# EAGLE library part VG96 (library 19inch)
PCB EUROCARD, 96-pin type C/ABC, 2.54 mm

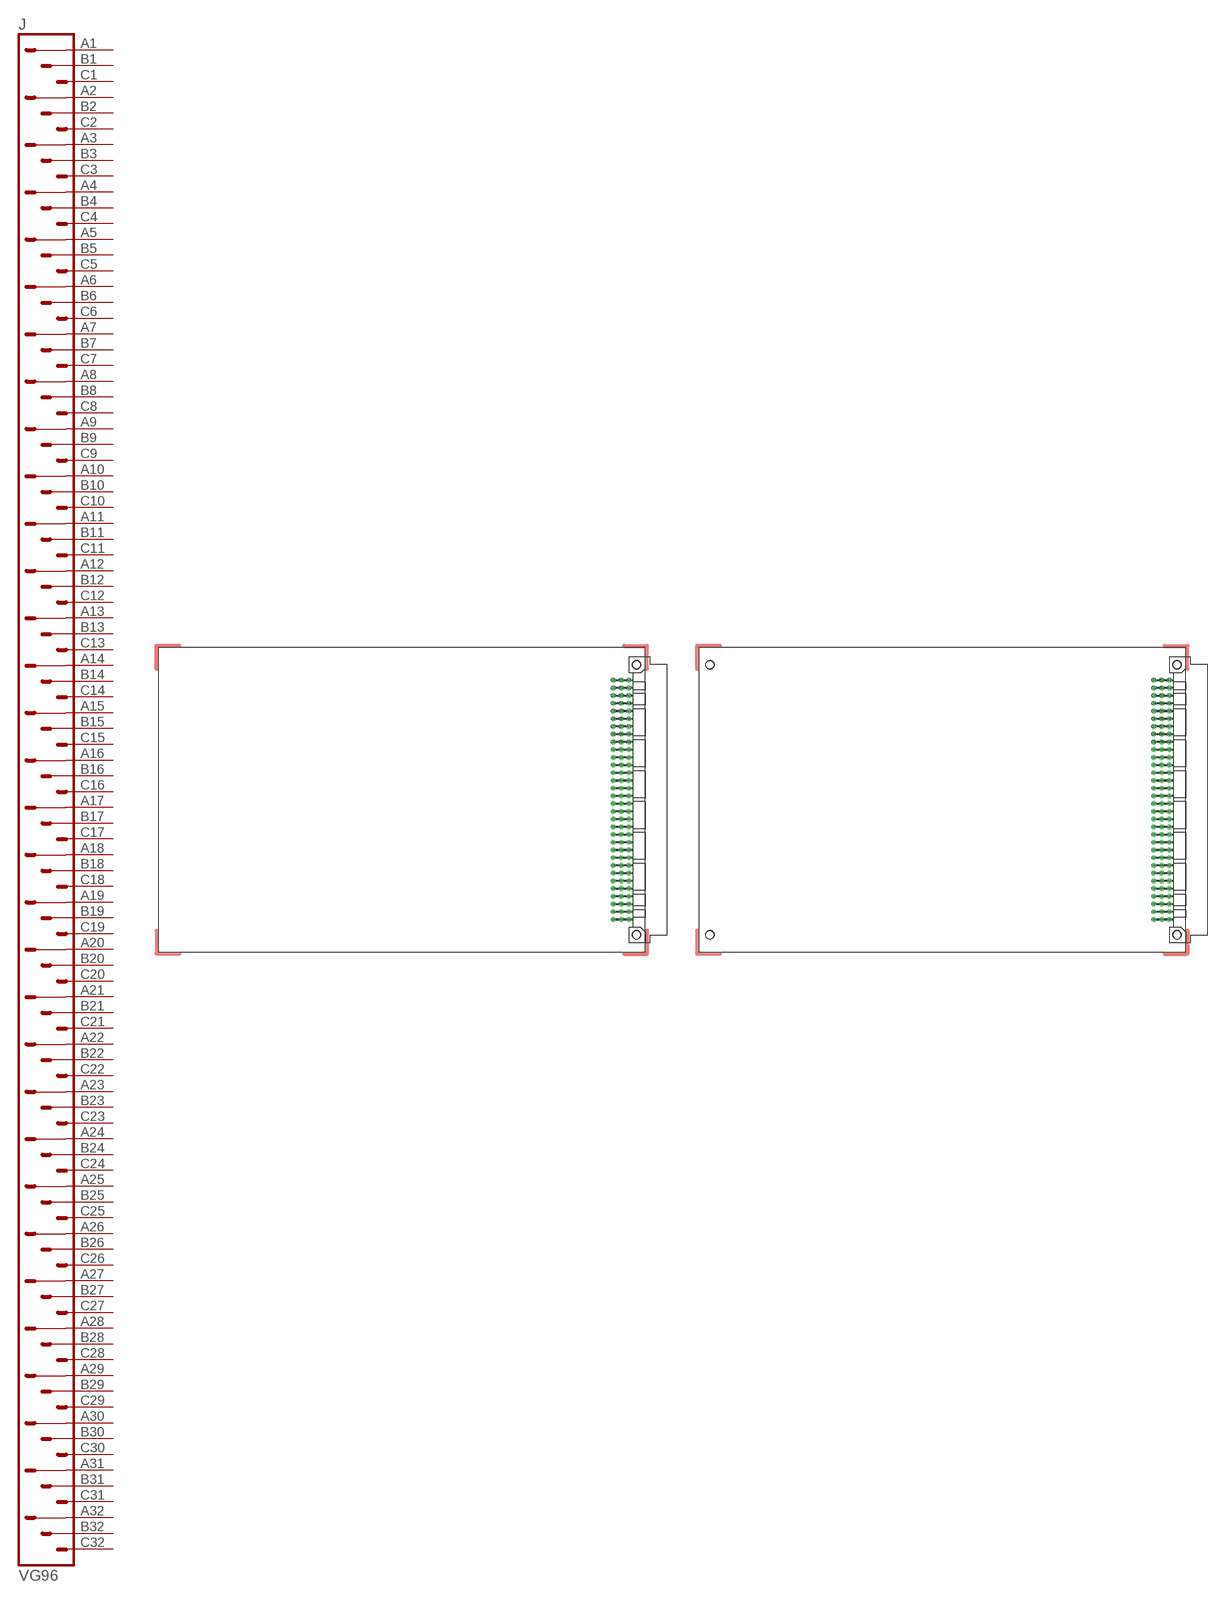
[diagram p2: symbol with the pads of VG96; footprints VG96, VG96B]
Designator prefix J

## VG96  [VG96]
A1  A1  pas
A2  A2  pas
A3  A3  pas
A4  A4  pas
A5  A5  pas
A6  A6  pas
A7  A7  pas
A8  A8  pas
A9  A9  pas
A10  A10  pas
A11  A11  pas
A12  A12  pas
A13  A13  pas
A14  A14  pas
A15  A15  pas
A16  A16  pas
A17  A17  pas
A18  A18  pas
A19  A19  pas
A20  A20  pas
A21  A21  pas
A22  A22  pas
A23  A23  pas
A24  A24  pas
A25  A25  pas
A26  A26  pas
A27  A27  pas
A28  A28  pas
A29  A29  pas
A30  A30  pas
A31  A31  pas
A32  A32  pas
B1  B1  pas
B2  B2  pas
B3  B3  pas
B4  B4  pas
B5  B5  pas
B6  B6  pas
B7  B7  pas
B8  B8  pas
B9  B9  pas
B10  B10  pas
B11  B11  pas
B12  B12  pas
B13  B13  pas
B14  B14  pas
B15  B15  pas
B16  B16  pas
B17  B17  pas
B18  B18  pas
B19  B19  pas
B20  B20  pas
B21  B21  pas
B22  B22  pas
B23  B23  pas
B24  B24  pas
B25  B25  pas
B26  B26  pas
B27  B27  pas
B28  B28  pas
B29  B29  pas
B30  B30  pas
B31  B31  pas
B32  B32  pas
C1  C1  pas
C2  C2  pas
C3  C3  pas
C4  C4  pas
C5  C5  pas
C6  C6  pas
C7  C7  pas
C8  C8  pas
C9  C9  pas
C10  C10  pas
C11  C11  pas
C12  C12  pas
C13  C13  pas
C14  C14  pas
C15  C15  pas
C16  C16  pas
C17  C17  pas
C18  C18  pas
C19  C19  pas
C20  C20  pas
C21  C21  pas
C22  C22  pas
C23  C23  pas
C24  C24  pas
C25  C25  pas
C26  C26  pas
C27  C27  pas
C28  C28  pas
C29  C29  pas
C30  C30  pas
C31  C31  pas
C32  C32  pas

## VG96B  [VG96B]
Pads as for VG96

## VG96K  [VG96K]
Pads as for VG96

## VG96KB  [VG96KB]
Pads as for VG96

## VG96P  [VG96P]
Pads as for VG96

## Footprint VG96 (pad centres in mm)
EUROCARD, C/ABC, 2.54
drill 0.914 pad 1.6 round: A1 154.94,39.37
drill 0.914 pad 1.6 octagon: A2 154.94,36.83; A3 154.94,34.29; A4 154.94,31.75; A5 154.94,29.21; A6 154.94,26.67; A7 154.94,24.13; A8 154.94,21.59; A9 154.94,19.05; A10 154.94,16.51; A11 154.94,13.97; A12 154.94,11.43; A13 154.94,8.89; A14 154.94,6.35; A15 154.94,3.81; A16 154.94,1.27; A17 154.94,-1.27; A18 154.94,-3.81; A19 154.94,-6.35; A20 154.94,-8.89; A21 154.94,-11.43; A22 154.94,-13.97; A23 154.94,-16.51; A24 154.94,-19.05; A25 154.94,-21.59; A26 154.94,-24.13; A27 154.94,-26.67; A28 154.94,-29.21; A29 154.94,-31.75; A30 154.94,-34.29; A31 154.94,-36.83; A32 154.94,-39.37; B1 152.4,39.37; B2 152.4,36.83; B3 152.4,34.29; B4 152.4,31.75; B5 152.4,29.21; B6 152.4,26.67; B7 152.4,24.13; B8 152.4,21.59; B9 152.4,19.05; B10 152.4,16.51; B11 152.4,13.97; B12 152.4,11.43; B13 152.4,8.89; B14 152.4,6.35; B15 152.4,3.81; B16 152.4,1.27; B17 152.4,-1.27; B18 152.4,-3.81; B19 152.4,-6.35; B20 152.4,-8.89; B21 152.4,-11.43; B22 152.4,-13.97; B23 152.4,-16.51; B24 152.4,-19.05; B25 152.4,-21.59; B26 152.4,-24.13; B27 152.4,-26.67; B28 152.4,-29.21; B29 152.4,-31.75; B30 152.4,-34.29; B31 152.4,-36.83; B32 152.4,-39.37; C1 149.86,39.37; C2 149.86,36.83; C3 149.86,34.29; C4 149.86,31.75; C5 149.86,29.21; C6 149.86,26.67; C7 149.86,24.13; C8 149.86,21.59; C9 149.86,19.05; C10 149.86,16.51; C11 149.86,13.97; C12 149.86,11.43; C13 149.86,8.89; C14 149.86,6.35; C15 149.86,3.81; C16 149.86,1.27; C17 149.86,-1.27; C18 149.86,-3.81; C19 149.86,-6.35; C20 149.86,-8.89; C21 149.86,-11.43; C22 149.86,-13.97; C23 149.86,-16.51; C24 149.86,-19.05; C25 149.86,-21.59; C26 149.86,-24.13; C27 149.86,-26.67; C28 149.86,-29.21; C29 149.86,-31.75; C30 149.86,-34.29; C31 149.86,-36.83; C32 149.86,-39.37
hole 2.794 at 157.48,44.45
hole 2.794 at 157.48,-44.45

## Footprint VG96B (pad centres in mm)
EUROCARD, 4 holes, C/ABC, 2.54
drill 0.914 pad 1.6 round: A1 154.94,39.37
drill 0.914 pad 1.6 octagon: A2 154.94,36.83; A3 154.94,34.29; A4 154.94,31.75; A5 154.94,29.21; A6 154.94,26.67; A7 154.94,24.13; A8 154.94,21.59; A9 154.94,19.05; A10 154.94,16.51; A11 154.94,13.97; A12 154.94,11.43; A13 154.94,8.89; A14 154.94,6.35; A15 154.94,3.81; A16 154.94,1.27; A17 154.94,-1.27; A18 154.94,-3.81; A19 154.94,-6.35; A20 154.94,-8.89; A21 154.94,-11.43; A22 154.94,-13.97; A23 154.94,-16.51; A24 154.94,-19.05; A25 154.94,-21.59; A26 154.94,-24.13; A27 154.94,-26.67; A28 154.94,-29.21; A29 154.94,-31.75; A30 154.94,-34.29; A31 154.94,-36.83; A32 154.94,-39.37; B1 152.4,39.37; B2 152.4,36.83; B3 152.4,34.29; B4 152.4,31.75; B5 152.4,29.21; B6 152.4,26.67; B7 152.4,24.13; B8 152.4,21.59; B9 152.4,19.05; B10 152.4,16.51; B11 152.4,13.97; B12 152.4,11.43; B13 152.4,8.89; B14 152.4,6.35; B15 152.4,3.81; B16 152.4,1.27; B17 152.4,-1.27; B18 152.4,-3.81; B19 152.4,-6.35; B20 152.4,-8.89; B21 152.4,-11.43; B22 152.4,-13.97; B23 152.4,-16.51; B24 152.4,-19.05; B25 152.4,-21.59; B26 152.4,-24.13; B27 152.4,-26.67; B28 152.4,-29.21; B29 152.4,-31.75; B30 152.4,-34.29; B31 152.4,-36.83; B32 152.4,-39.37; C1 149.86,39.37; C2 149.86,36.83; C3 149.86,34.29; C4 149.86,31.75; C5 149.86,29.21; C6 149.86,26.67; C7 149.86,24.13; C8 149.86,21.59; C9 149.86,19.05; C10 149.86,16.51; C11 149.86,13.97; C12 149.86,11.43; C13 149.86,8.89; C14 149.86,6.35; C15 149.86,3.81; C16 149.86,1.27; C17 149.86,-1.27; C18 149.86,-3.81; C19 149.86,-6.35; C20 149.86,-8.89; C21 149.86,-11.43; C22 149.86,-13.97; C23 149.86,-16.51; C24 149.86,-19.05; C25 149.86,-21.59; C26 149.86,-24.13; C27 149.86,-26.67; C28 149.86,-29.21; C29 149.86,-31.75; C30 149.86,-34.29; C31 149.86,-36.83; C32 149.86,-39.37
hole 2.794 at 157.48,44.45
hole 2.794 at 157.48,-44.45
hole 2.794 at 3.81,44.45
hole 2.794 at 3.81,-44.45

## Footprint VG96K (pad centres in mm)
EUROCARD, 2 holes, C/ABC, 2.54
drill 0.914 pad 1.6 round: A1 154.94,39.37
drill 0.914 pad 1.6 octagon: A2 154.94,36.83; A3 154.94,34.29; A4 154.94,31.75; A5 154.94,29.21; A6 154.94,26.67; A7 154.94,24.13; A8 154.94,21.59; A9 154.94,19.05; A10 154.94,16.51; A11 154.94,13.97; A12 154.94,11.43; A13 154.94,8.89; A14 154.94,6.35; A15 154.94,3.81; A16 154.94,1.27; A17 154.94,-1.27; A18 154.94,-3.81; A19 154.94,-6.35; A20 154.94,-8.89; A21 154.94,-11.43; A22 154.94,-13.97; A23 154.94,-16.51; A24 154.94,-19.05; A25 154.94,-21.59; A26 154.94,-24.13; A27 154.94,-26.67; A28 154.94,-29.21; A29 154.94,-31.75; A30 154.94,-34.29; A31 154.94,-36.83; A32 154.94,-39.37; B1 152.4,39.37; B2 152.4,36.83; B3 152.4,34.29; B4 152.4,31.75; B5 152.4,29.21; B6 152.4,26.67; B7 152.4,24.13; B8 152.4,21.59; B9 152.4,19.05; B10 152.4,16.51; B11 152.4,13.97; B12 152.4,11.43; B13 152.4,8.89; B14 152.4,6.35; B15 152.4,3.81; B16 152.4,1.27; B17 152.4,-1.27; B18 152.4,-3.81; B19 152.4,-6.35; B20 152.4,-8.89; B21 152.4,-11.43; B22 152.4,-13.97; B23 152.4,-16.51; B24 152.4,-19.05; B25 152.4,-21.59; B26 152.4,-24.13; B27 152.4,-26.67; B28 152.4,-29.21; B29 152.4,-31.75; B30 152.4,-34.29; B31 152.4,-36.83; B32 152.4,-39.37; C1 149.86,39.37; C2 149.86,36.83; C3 149.86,34.29; C4 149.86,31.75; C5 149.86,29.21; C6 149.86,26.67; C7 149.86,24.13; C8 149.86,21.59; C9 149.86,19.05; C10 149.86,16.51; C11 149.86,13.97; C12 149.86,11.43; C13 149.86,8.89; C14 149.86,6.35; C15 149.86,3.81; C16 149.86,1.27; C17 149.86,-1.27; C18 149.86,-3.81; C19 149.86,-6.35; C20 149.86,-8.89; C21 149.86,-11.43; C22 149.86,-13.97; C23 149.86,-16.51; C24 149.86,-19.05; C25 149.86,-21.59; C26 149.86,-24.13; C27 149.86,-26.67; C28 149.86,-29.21; C29 149.86,-31.75; C30 149.86,-34.29; C31 149.86,-36.83; C32 149.86,-39.37
hole 2.794 at 157.48,44.45
hole 2.794 at 157.48,-44.45

## Footprint VG96KB (pad centres in mm)
EUROCARD, 4 holes, C/ABC, 2.54
drill 0.914 pad 1.6 round: A1 154.94,39.37
drill 0.914 pad 1.6 octagon: A2 154.94,36.83; A3 154.94,34.29; A4 154.94,31.75; A5 154.94,29.21; A6 154.94,26.67; A7 154.94,24.13; A8 154.94,21.59; A9 154.94,19.05; A10 154.94,16.51; A11 154.94,13.97; A12 154.94,11.43; A13 154.94,8.89; A14 154.94,6.35; A15 154.94,3.81; A16 154.94,1.27; A17 154.94,-1.27; A18 154.94,-3.81; A19 154.94,-6.35; A20 154.94,-8.89; A21 154.94,-11.43; A22 154.94,-13.97; A23 154.94,-16.51; A24 154.94,-19.05; A25 154.94,-21.59; A26 154.94,-24.13; A27 154.94,-26.67; A28 154.94,-29.21; A29 154.94,-31.75; A30 154.94,-34.29; A31 154.94,-36.83; A32 154.94,-39.37; B1 152.4,39.37; B2 152.4,36.83; B3 152.4,34.29; B4 152.4,31.75; B5 152.4,29.21; B6 152.4,26.67; B7 152.4,24.13; B8 152.4,21.59; B9 152.4,19.05; B10 152.4,16.51; B11 152.4,13.97; B12 152.4,11.43; B13 152.4,8.89; B14 152.4,6.35; B15 152.4,3.81; B16 152.4,1.27; B17 152.4,-1.27; B18 152.4,-3.81; B19 152.4,-6.35; B20 152.4,-8.89; B21 152.4,-11.43; B22 152.4,-13.97; B23 152.4,-16.51; B24 152.4,-19.05; B25 152.4,-21.59; B26 152.4,-24.13; B27 152.4,-26.67; B28 152.4,-29.21; B29 152.4,-31.75; B30 152.4,-34.29; B31 152.4,-36.83; B32 152.4,-39.37; C1 149.86,39.37; C2 149.86,36.83; C3 149.86,34.29; C4 149.86,31.75; C5 149.86,29.21; C6 149.86,26.67; C7 149.86,24.13; C8 149.86,21.59; C9 149.86,19.05; C10 149.86,16.51; C11 149.86,13.97; C12 149.86,11.43; C13 149.86,8.89; C14 149.86,6.35; C15 149.86,3.81; C16 149.86,1.27; C17 149.86,-1.27; C18 149.86,-3.81; C19 149.86,-6.35; C20 149.86,-8.89; C21 149.86,-11.43; C22 149.86,-13.97; C23 149.86,-16.51; C24 149.86,-19.05; C25 149.86,-21.59; C26 149.86,-24.13; C27 149.86,-26.67; C28 149.86,-29.21; C29 149.86,-31.75; C30 149.86,-34.29; C31 149.86,-36.83; C32 149.86,-39.37
hole 2.794 at 157.48,44.45
hole 2.794 at 157.48,-44.45
hole 2.794 at 3.81,44.45
hole 2.794 at 3.81,-44.45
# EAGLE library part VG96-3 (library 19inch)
PCB EUROCARD, 96-pin type C/ABC, 2.54 mm

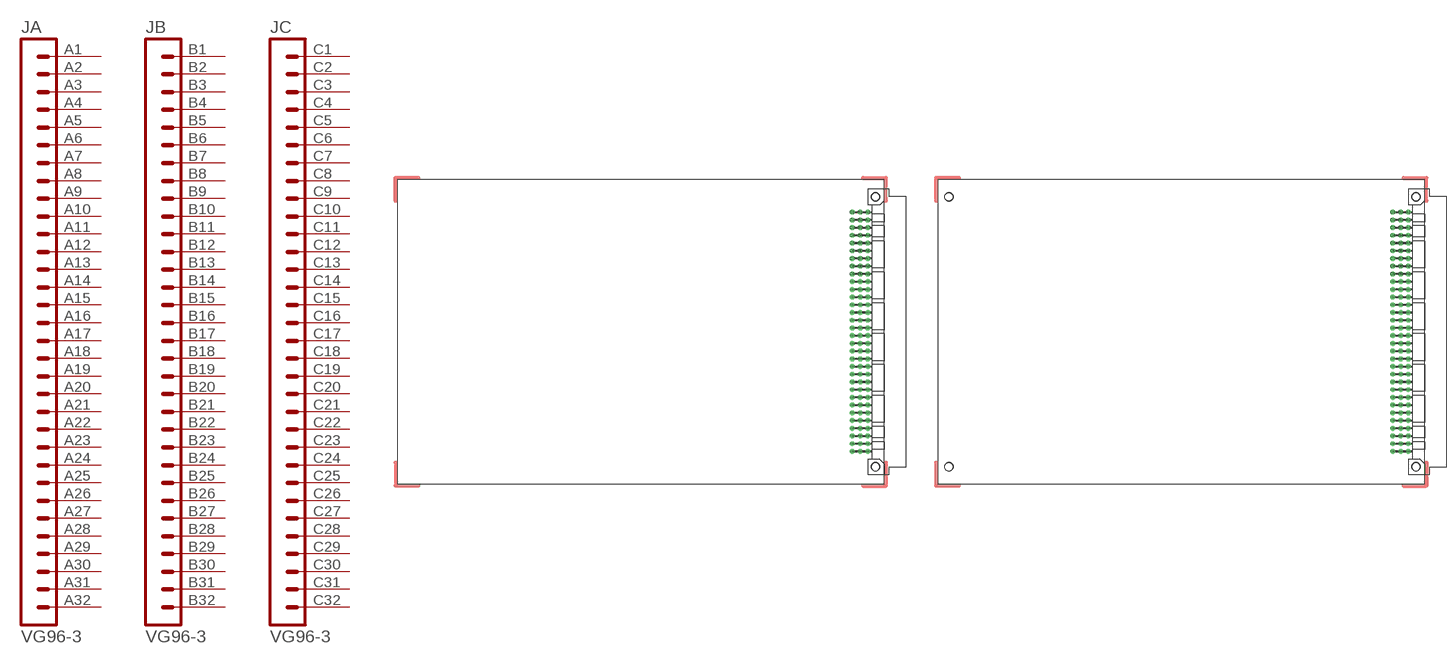
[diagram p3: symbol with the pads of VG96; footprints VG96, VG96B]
Designator prefix J; gates A=M32 B=M32 C=M32

## VG96-3  [VG96]
A1  A:1  pas
A2  A:2  pas
A3  A:3  pas
A4  A:4  pas
A5  A:5  pas
A6  A:6  pas
A7  A:7  pas
A8  A:8  pas
A9  A:9  pas
A10  A:10  pas
A11  A:11  pas
A12  A:12  pas
A13  A:13  pas
A14  A:14  pas
A15  A:15  pas
A16  A:16  pas
A17  A:17  pas
A18  A:18  pas
A19  A:19  pas
A20  A:20  pas
A21  A:21  pas
A22  A:22  pas
A23  A:23  pas
A24  A:24  pas
A25  A:25  pas
A26  A:26  pas
A27  A:27  pas
A28  A:28  pas
A29  A:29  pas
A30  A:30  pas
A31  A:31  pas
A32  A:32  pas
B1  B:1  pas
B2  B:2  pas
B3  B:3  pas
B4  B:4  pas
B5  B:5  pas
B6  B:6  pas
B7  B:7  pas
B8  B:8  pas
B9  B:9  pas
B10  B:10  pas
B11  B:11  pas
B12  B:12  pas
B13  B:13  pas
B14  B:14  pas
B15  B:15  pas
B16  B:16  pas
B17  B:17  pas
B18  B:18  pas
B19  B:19  pas
B20  B:20  pas
B21  B:21  pas
B22  B:22  pas
B23  B:23  pas
B24  B:24  pas
B25  B:25  pas
B26  B:26  pas
B27  B:27  pas
B28  B:28  pas
B29  B:29  pas
B30  B:30  pas
B31  B:31  pas
B32  B:32  pas
C1  C:1  pas
C2  C:2  pas
C3  C:3  pas
C4  C:4  pas
C5  C:5  pas
C6  C:6  pas
C7  C:7  pas
C8  C:8  pas
C9  C:9  pas
C10  C:10  pas
C11  C:11  pas
C12  C:12  pas
C13  C:13  pas
C14  C:14  pas
C15  C:15  pas
C16  C:16  pas
C17  C:17  pas
C18  C:18  pas
C19  C:19  pas
C20  C:20  pas
C21  C:21  pas
C22  C:22  pas
C23  C:23  pas
C24  C:24  pas
C25  C:25  pas
C26  C:26  pas
C27  C:27  pas
C28  C:28  pas
C29  C:29  pas
C30  C:30  pas
C31  C:31  pas
C32  C:32  pas

## VG96-3B  [VG96B]
Pads as for VG96

## VG96-3K  [VG96K]
Pads as for VG96

## VG96-3KB  [VG96KB]
Pads as for VG96

## VG96-3P  [VG96P]
Pads as for VG96

## Footprint VG96 (pad centres in mm)
EUROCARD, C/ABC, 2.54
drill 0.914 pad 1.6 round: A1 154.94,39.37
drill 0.914 pad 1.6 octagon: A2 154.94,36.83; A3 154.94,34.29; A4 154.94,31.75; A5 154.94,29.21; A6 154.94,26.67; A7 154.94,24.13; A8 154.94,21.59; A9 154.94,19.05; A10 154.94,16.51; A11 154.94,13.97; A12 154.94,11.43; A13 154.94,8.89; A14 154.94,6.35; A15 154.94,3.81; A16 154.94,1.27; A17 154.94,-1.27; A18 154.94,-3.81; A19 154.94,-6.35; A20 154.94,-8.89; A21 154.94,-11.43; A22 154.94,-13.97; A23 154.94,-16.51; A24 154.94,-19.05; A25 154.94,-21.59; A26 154.94,-24.13; A27 154.94,-26.67; A28 154.94,-29.21; A29 154.94,-31.75; A30 154.94,-34.29; A31 154.94,-36.83; A32 154.94,-39.37; B1 152.4,39.37; B2 152.4,36.83; B3 152.4,34.29; B4 152.4,31.75; B5 152.4,29.21; B6 152.4,26.67; B7 152.4,24.13; B8 152.4,21.59; B9 152.4,19.05; B10 152.4,16.51; B11 152.4,13.97; B12 152.4,11.43; B13 152.4,8.89; B14 152.4,6.35; B15 152.4,3.81; B16 152.4,1.27; B17 152.4,-1.27; B18 152.4,-3.81; B19 152.4,-6.35; B20 152.4,-8.89; B21 152.4,-11.43; B22 152.4,-13.97; B23 152.4,-16.51; B24 152.4,-19.05; B25 152.4,-21.59; B26 152.4,-24.13; B27 152.4,-26.67; B28 152.4,-29.21; B29 152.4,-31.75; B30 152.4,-34.29; B31 152.4,-36.83; B32 152.4,-39.37; C1 149.86,39.37; C2 149.86,36.83; C3 149.86,34.29; C4 149.86,31.75; C5 149.86,29.21; C6 149.86,26.67; C7 149.86,24.13; C8 149.86,21.59; C9 149.86,19.05; C10 149.86,16.51; C11 149.86,13.97; C12 149.86,11.43; C13 149.86,8.89; C14 149.86,6.35; C15 149.86,3.81; C16 149.86,1.27; C17 149.86,-1.27; C18 149.86,-3.81; C19 149.86,-6.35; C20 149.86,-8.89; C21 149.86,-11.43; C22 149.86,-13.97; C23 149.86,-16.51; C24 149.86,-19.05; C25 149.86,-21.59; C26 149.86,-24.13; C27 149.86,-26.67; C28 149.86,-29.21; C29 149.86,-31.75; C30 149.86,-34.29; C31 149.86,-36.83; C32 149.86,-39.37
hole 2.794 at 157.48,44.45
hole 2.794 at 157.48,-44.45

## Footprint VG96B (pad centres in mm)
EUROCARD, 4 holes, C/ABC, 2.54
drill 0.914 pad 1.6 round: A1 154.94,39.37
drill 0.914 pad 1.6 octagon: A2 154.94,36.83; A3 154.94,34.29; A4 154.94,31.75; A5 154.94,29.21; A6 154.94,26.67; A7 154.94,24.13; A8 154.94,21.59; A9 154.94,19.05; A10 154.94,16.51; A11 154.94,13.97; A12 154.94,11.43; A13 154.94,8.89; A14 154.94,6.35; A15 154.94,3.81; A16 154.94,1.27; A17 154.94,-1.27; A18 154.94,-3.81; A19 154.94,-6.35; A20 154.94,-8.89; A21 154.94,-11.43; A22 154.94,-13.97; A23 154.94,-16.51; A24 154.94,-19.05; A25 154.94,-21.59; A26 154.94,-24.13; A27 154.94,-26.67; A28 154.94,-29.21; A29 154.94,-31.75; A30 154.94,-34.29; A31 154.94,-36.83; A32 154.94,-39.37; B1 152.4,39.37; B2 152.4,36.83; B3 152.4,34.29; B4 152.4,31.75; B5 152.4,29.21; B6 152.4,26.67; B7 152.4,24.13; B8 152.4,21.59; B9 152.4,19.05; B10 152.4,16.51; B11 152.4,13.97; B12 152.4,11.43; B13 152.4,8.89; B14 152.4,6.35; B15 152.4,3.81; B16 152.4,1.27; B17 152.4,-1.27; B18 152.4,-3.81; B19 152.4,-6.35; B20 152.4,-8.89; B21 152.4,-11.43; B22 152.4,-13.97; B23 152.4,-16.51; B24 152.4,-19.05; B25 152.4,-21.59; B26 152.4,-24.13; B27 152.4,-26.67; B28 152.4,-29.21; B29 152.4,-31.75; B30 152.4,-34.29; B31 152.4,-36.83; B32 152.4,-39.37; C1 149.86,39.37; C2 149.86,36.83; C3 149.86,34.29; C4 149.86,31.75; C5 149.86,29.21; C6 149.86,26.67; C7 149.86,24.13; C8 149.86,21.59; C9 149.86,19.05; C10 149.86,16.51; C11 149.86,13.97; C12 149.86,11.43; C13 149.86,8.89; C14 149.86,6.35; C15 149.86,3.81; C16 149.86,1.27; C17 149.86,-1.27; C18 149.86,-3.81; C19 149.86,-6.35; C20 149.86,-8.89; C21 149.86,-11.43; C22 149.86,-13.97; C23 149.86,-16.51; C24 149.86,-19.05; C25 149.86,-21.59; C26 149.86,-24.13; C27 149.86,-26.67; C28 149.86,-29.21; C29 149.86,-31.75; C30 149.86,-34.29; C31 149.86,-36.83; C32 149.86,-39.37
hole 2.794 at 157.48,44.45
hole 2.794 at 157.48,-44.45
hole 2.794 at 3.81,44.45
hole 2.794 at 3.81,-44.45

## Footprint VG96K (pad centres in mm)
EUROCARD, 2 holes, C/ABC, 2.54
drill 0.914 pad 1.6 round: A1 154.94,39.37
drill 0.914 pad 1.6 octagon: A2 154.94,36.83; A3 154.94,34.29; A4 154.94,31.75; A5 154.94,29.21; A6 154.94,26.67; A7 154.94,24.13; A8 154.94,21.59; A9 154.94,19.05; A10 154.94,16.51; A11 154.94,13.97; A12 154.94,11.43; A13 154.94,8.89; A14 154.94,6.35; A15 154.94,3.81; A16 154.94,1.27; A17 154.94,-1.27; A18 154.94,-3.81; A19 154.94,-6.35; A20 154.94,-8.89; A21 154.94,-11.43; A22 154.94,-13.97; A23 154.94,-16.51; A24 154.94,-19.05; A25 154.94,-21.59; A26 154.94,-24.13; A27 154.94,-26.67; A28 154.94,-29.21; A29 154.94,-31.75; A30 154.94,-34.29; A31 154.94,-36.83; A32 154.94,-39.37; B1 152.4,39.37; B2 152.4,36.83; B3 152.4,34.29; B4 152.4,31.75; B5 152.4,29.21; B6 152.4,26.67; B7 152.4,24.13; B8 152.4,21.59; B9 152.4,19.05; B10 152.4,16.51; B11 152.4,13.97; B12 152.4,11.43; B13 152.4,8.89; B14 152.4,6.35; B15 152.4,3.81; B16 152.4,1.27; B17 152.4,-1.27; B18 152.4,-3.81; B19 152.4,-6.35; B20 152.4,-8.89; B21 152.4,-11.43; B22 152.4,-13.97; B23 152.4,-16.51; B24 152.4,-19.05; B25 152.4,-21.59; B26 152.4,-24.13; B27 152.4,-26.67; B28 152.4,-29.21; B29 152.4,-31.75; B30 152.4,-34.29; B31 152.4,-36.83; B32 152.4,-39.37; C1 149.86,39.37; C2 149.86,36.83; C3 149.86,34.29; C4 149.86,31.75; C5 149.86,29.21; C6 149.86,26.67; C7 149.86,24.13; C8 149.86,21.59; C9 149.86,19.05; C10 149.86,16.51; C11 149.86,13.97; C12 149.86,11.43; C13 149.86,8.89; C14 149.86,6.35; C15 149.86,3.81; C16 149.86,1.27; C17 149.86,-1.27; C18 149.86,-3.81; C19 149.86,-6.35; C20 149.86,-8.89; C21 149.86,-11.43; C22 149.86,-13.97; C23 149.86,-16.51; C24 149.86,-19.05; C25 149.86,-21.59; C26 149.86,-24.13; C27 149.86,-26.67; C28 149.86,-29.21; C29 149.86,-31.75; C30 149.86,-34.29; C31 149.86,-36.83; C32 149.86,-39.37
hole 2.794 at 157.48,44.45
hole 2.794 at 157.48,-44.45

## Footprint VG96KB (pad centres in mm)
EUROCARD, 4 holes, C/ABC, 2.54
drill 0.914 pad 1.6 round: A1 154.94,39.37
drill 0.914 pad 1.6 octagon: A2 154.94,36.83; A3 154.94,34.29; A4 154.94,31.75; A5 154.94,29.21; A6 154.94,26.67; A7 154.94,24.13; A8 154.94,21.59; A9 154.94,19.05; A10 154.94,16.51; A11 154.94,13.97; A12 154.94,11.43; A13 154.94,8.89; A14 154.94,6.35; A15 154.94,3.81; A16 154.94,1.27; A17 154.94,-1.27; A18 154.94,-3.81; A19 154.94,-6.35; A20 154.94,-8.89; A21 154.94,-11.43; A22 154.94,-13.97; A23 154.94,-16.51; A24 154.94,-19.05; A25 154.94,-21.59; A26 154.94,-24.13; A27 154.94,-26.67; A28 154.94,-29.21; A29 154.94,-31.75; A30 154.94,-34.29; A31 154.94,-36.83; A32 154.94,-39.37; B1 152.4,39.37; B2 152.4,36.83; B3 152.4,34.29; B4 152.4,31.75; B5 152.4,29.21; B6 152.4,26.67; B7 152.4,24.13; B8 152.4,21.59; B9 152.4,19.05; B10 152.4,16.51; B11 152.4,13.97; B12 152.4,11.43; B13 152.4,8.89; B14 152.4,6.35; B15 152.4,3.81; B16 152.4,1.27; B17 152.4,-1.27; B18 152.4,-3.81; B19 152.4,-6.35; B20 152.4,-8.89; B21 152.4,-11.43; B22 152.4,-13.97; B23 152.4,-16.51; B24 152.4,-19.05; B25 152.4,-21.59; B26 152.4,-24.13; B27 152.4,-26.67; B28 152.4,-29.21; B29 152.4,-31.75; B30 152.4,-34.29; B31 152.4,-36.83; B32 152.4,-39.37; C1 149.86,39.37; C2 149.86,36.83; C3 149.86,34.29; C4 149.86,31.75; C5 149.86,29.21; C6 149.86,26.67; C7 149.86,24.13; C8 149.86,21.59; C9 149.86,19.05; C10 149.86,16.51; C11 149.86,13.97; C12 149.86,11.43; C13 149.86,8.89; C14 149.86,6.35; C15 149.86,3.81; C16 149.86,1.27; C17 149.86,-1.27; C18 149.86,-3.81; C19 149.86,-6.35; C20 149.86,-8.89; C21 149.86,-11.43; C22 149.86,-13.97; C23 149.86,-16.51; C24 149.86,-19.05; C25 149.86,-21.59; C26 149.86,-24.13; C27 149.86,-26.67; C28 149.86,-29.21; C29 149.86,-31.75; C30 149.86,-34.29; C31 149.86,-36.83; C32 149.86,-39.37
hole 2.794 at 157.48,44.45
hole 2.794 at 157.48,-44.45
hole 2.794 at 3.81,44.45
hole 2.794 at 3.81,-44.45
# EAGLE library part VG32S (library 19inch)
PCB EUROCARD, 32-pin type C/AC, 5.08 mm

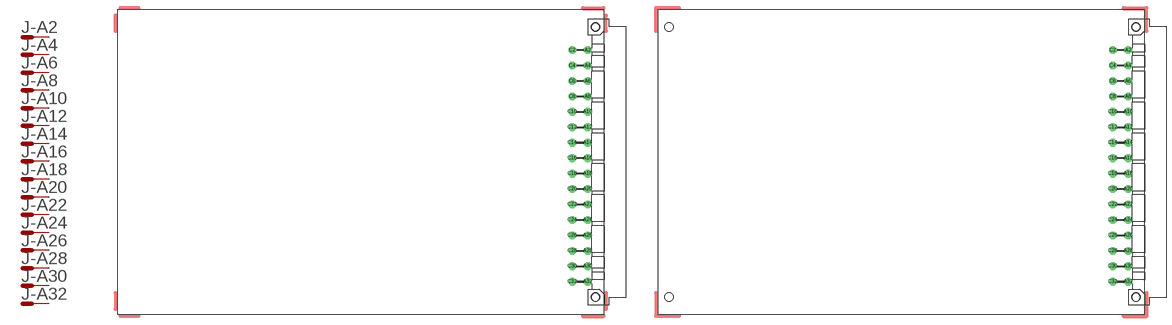
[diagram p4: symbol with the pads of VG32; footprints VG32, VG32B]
Designator prefix J; gates -A2=MS -A4=MS -A6=MS -A8=MS -A10=MS -A12=MS -A14=MS -A16=MS -A18=MS -A20=MS -A22=MS -A24=MS -A26=MS -A28=MS -A30=MS -A32=MS -C2=MS -C4=MS -C6=MS -C8=MS -C10=MS -C12=MS -C14=MS -C16=MS -C18=MS -C20=MS -C22=MS -C24=MS -C26=MS -C28=MS -C30=MS -C32=MSV

## VG32S  [VG32]
A2  -A2:MS  pas
A4  -A4:MS  pas
A6  -A6:MS  pas
A8  -A8:MS  pas
A10  -A10:MS  pas
A12  -A12:MS  pas
A14  -A14:MS  pas
A16  -A16:MS  pas
A18  -A18:MS  pas
A20  -A20:MS  pas
A22  -A22:MS  pas
A24  -A24:MS  pas
A26  -A26:MS  pas
A28  -A28:MS  pas
A30  -A30:MS  pas
A32  -A32:MS  pas
C2  -C2:MS  pas
C4  -C4:MS  pas
C6  -C6:MS  pas
C8  -C8:MS  pas
C10  -C10:MS  pas
C12  -C12:MS  pas
C14  -C14:MS  pas
C16  -C16:MS  pas
C18  -C18:MS  pas
C20  -C20:MS  pas
C22  -C22:MS  pas
C24  -C24:MS  pas
C26  -C26:MS  pas
C28  -C28:MS  pas
C30  -C30:MS  pas
C32  -C32:MSV  pas

## VG32SB  [VG32B]
Pads as for VG32

## VG32SK  [VG32K]
Pads as for VG32

## VG32SKB  [VG32KB]
Pads as for VG32

## VG32SP  [VG32P]
Pads as for VG32

## Footprint VG32 (pad centres in mm)
EUROCARD, C/AC, 5.08
drill 1.016 pad 2.54 octagon: A2 154.94,36.83; A4 154.94,31.75; A6 154.94,26.67; A8 154.94,21.59; A10 154.94,16.51; A12 154.94,11.43; A14 154.94,6.35; A16 154.94,1.27; A18 154.94,-3.81; A20 154.94,-8.89; A22 154.94,-13.97; A24 154.94,-19.05; A26 154.94,-24.13; A28 154.94,-29.21; A30 154.94,-34.29; A32 154.94,-39.37; C2 149.86,36.83; C4 149.86,31.75; C6 149.86,26.67; C8 149.86,21.59; C10 149.86,16.51; C12 149.86,11.43; C14 149.86,6.35; C16 149.86,1.27; C18 149.86,-3.81; C20 149.86,-8.89; C22 149.86,-13.97; C24 149.86,-19.05; C26 149.86,-24.13; C28 149.86,-29.21; C30 149.86,-34.29; C32 149.86,-39.37
hole 2.794 at 157.48,44.45
hole 2.794 at 157.48,-44.45

## Footprint VG32B (pad centres in mm)
EUROCARD, 4 mounting holes, C/AC, 5.08
drill 1.016 pad 2.54 octagon: A2 154.94,36.83; A4 154.94,31.75; A6 154.94,26.67; A8 154.94,21.59; A10 154.94,16.51; A12 154.94,11.43; A14 154.94,6.35; A16 154.94,1.27; A18 154.94,-3.81; A20 154.94,-8.89; A22 154.94,-13.97; A24 154.94,-19.05; A26 154.94,-24.13; A28 154.94,-29.21; A30 154.94,-34.29; A32 154.94,-39.37; C2 149.86,36.83; C4 149.86,31.75; C6 149.86,26.67; C8 149.86,21.59; C10 149.86,16.51; C12 149.86,11.43; C14 149.86,6.35; C16 149.86,1.27; C18 149.86,-3.81; C20 149.86,-8.89; C22 149.86,-13.97; C24 149.86,-19.05; C26 149.86,-24.13; C28 149.86,-29.21; C30 149.86,-34.29; C32 149.86,-39.37
hole 2.794 at 157.48,44.45
hole 2.794 at 157.48,-44.45
hole 2.794 at 3.81,-44.45
hole 2.794 at 3.81,44.45

## Footprint VG32K (pad centres in mm)
EUROCARD, 2 mounting holes, C/AC, 5.08
drill 1.016 pad 2.54 octagon: A2 154.94,36.83; A4 154.94,31.75; A6 154.94,26.67; A8 154.94,21.59; A10 154.94,16.51; A12 154.94,11.43; A14 154.94,6.35; A16 154.94,1.27; A18 154.94,-3.81; A20 154.94,-8.89; A22 154.94,-13.97; A24 154.94,-19.05; A26 154.94,-24.13; A28 154.94,-29.21; A30 154.94,-34.29; A32 154.94,-39.37; C2 149.86,36.83; C4 149.86,31.75; C6 149.86,26.67; C8 149.86,21.59; C10 149.86,16.51; C12 149.86,11.43; C14 149.86,6.35; C16 149.86,1.27; C18 149.86,-3.81; C20 149.86,-8.89; C22 149.86,-13.97; C24 149.86,-19.05; C26 149.86,-24.13; C28 149.86,-29.21; C30 149.86,-34.29; C32 149.86,-39.37
hole 2.794 at 157.48,44.45
hole 2.794 at 157.48,-44.45

## Footprint VG32KB (pad centres in mm)
EUROCARD, 4 mounting holes, C/AC, 5.08
drill 1.016 pad 2.54 octagon: A2 154.94,36.83; A4 154.94,31.75; A6 154.94,26.67; A8 154.94,21.59; A10 154.94,16.51; A12 154.94,11.43; A14 154.94,6.35; A16 154.94,1.27; A18 154.94,-3.81; A20 154.94,-8.89; A22 154.94,-13.97; A24 154.94,-19.05; A26 154.94,-24.13; A28 154.94,-29.21; A30 154.94,-34.29; A32 154.94,-39.37; C2 149.86,36.83; C4 149.86,31.75; C6 149.86,26.67; C8 149.86,21.59; C10 149.86,16.51; C12 149.86,11.43; C14 149.86,6.35; C16 149.86,1.27; C18 149.86,-3.81; C20 149.86,-8.89; C22 149.86,-13.97; C24 149.86,-19.05; C26 149.86,-24.13; C28 149.86,-29.21; C30 149.86,-34.29; C32 149.86,-39.37
hole 2.794 at 157.48,44.45
hole 2.794 at 157.48,-44.45
hole 2.794 at 3.81,-44.45
hole 2.794 at 3.81,44.45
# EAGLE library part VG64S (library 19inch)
PCB EUROCARD, 64-pin type C/AC, 2.54 mm

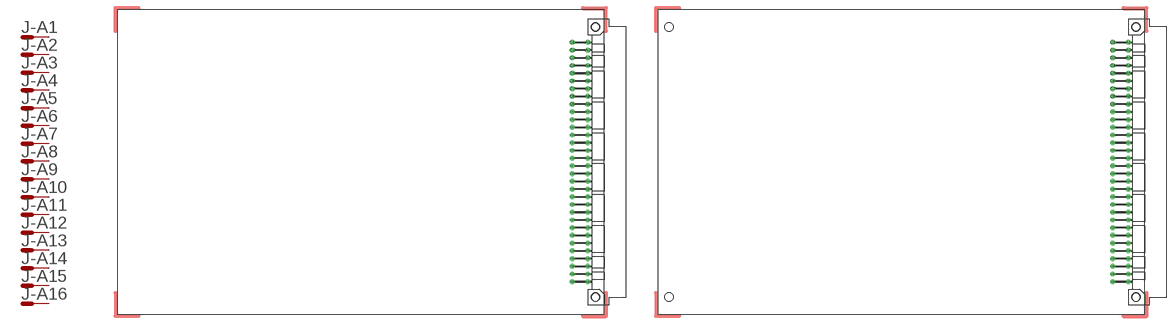
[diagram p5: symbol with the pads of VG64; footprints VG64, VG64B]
Designator prefix J; gates -A1=MS -A2=MS -A3=MS -A4=MS -A5=MS -A6=MS -A7=MS -A8=MS -A9=MS -A10=MS -A11=MS -A12=MS -A13=MS -A14=MS -A15=MS -A16=MS -A17=MS -A18=MS -A19=MS -A20=MS -A21=MS -A22=MS -A23=MS -A24=MS -A25=MS -A26=MS -A27=MS -A28=MS -A29=MS -A30=MS -A31=MS -A32=MS -C1=MS -C2=MS -C3=MS -C4=MS -C5=MS -C6=MS -C7=MS -C8=MS -C9=MS -C10=MS -C11=MS -C12=MS -C13=MS -C14=MS -C15=MS -C16=MS -C17=MS -C18=MS -C19=MS -C20=MS -C21=MS -C22=MS -C23=MS -C24=MS -C25=MS -C26=MS -C27=MS -C28=MS -C29=MS -C30=MS -C31=MS -C32=MSV

## VG64S  [VG64]
A1  -A1:MS  pas
A2  -A2:MS  pas
A3  -A3:MS  pas
A4  -A4:MS  pas
A5  -A5:MS  pas
A6  -A6:MS  pas
A7  -A7:MS  pas
A8  -A8:MS  pas
A9  -A9:MS  pas
A10  -A10:MS  pas
A11  -A11:MS  pas
A12  -A12:MS  pas
A13  -A13:MS  pas
A14  -A14:MS  pas
A15  -A15:MS  pas
A16  -A16:MS  pas
A17  -A17:MS  pas
A18  -A18:MS  pas
A19  -A19:MS  pas
A20  -A20:MS  pas
A21  -A21:MS  pas
A22  -A22:MS  pas
A23  -A23:MS  pas
A24  -A24:MS  pas
A25  -A25:MS  pas
A26  -A26:MS  pas
A27  -A27:MS  pas
A28  -A28:MS  pas
A29  -A29:MS  pas
A30  -A30:MS  pas
A31  -A31:MS  pas
A32  -A32:MS  pas
C1  -C1:MS  pas
C2  -C2:MS  pas
C3  -C3:MS  pas
C4  -C4:MS  pas
C5  -C5:MS  pas
C6  -C6:MS  pas
C7  -C7:MS  pas
C8  -C8:MS  pas
C9  -C9:MS  pas
C10  -C10:MS  pas
C11  -C11:MS  pas
C12  -C12:MS  pas
C13  -C13:MS  pas
C14  -C14:MS  pas
C15  -C15:MS  pas
C16  -C16:MS  pas
C17  -C17:MS  pas
C18  -C18:MS  pas
C19  -C19:MS  pas
C20  -C20:MS  pas
C21  -C21:MS  pas
C22  -C22:MS  pas
C23  -C23:MS  pas
C24  -C24:MS  pas
C25  -C25:MS  pas
C26  -C26:MS  pas
C27  -C27:MS  pas
C28  -C28:MS  pas
C29  -C29:MS  pas
C30  -C30:MS  pas
C31  -C31:MS  pas
C32  -C32:MSV  pas

## VG64SB  [VG64B]
Pads as for VG64

## VG64SK  [VG64K]
Pads as for VG64

## VG64SKB  [VG64KB]
Pads as for VG64

## VG64SP  [VG96P]
Pads as for VG64

## Footprint VG64 (pad centres in mm)
EUROCARD, 2 holes, C/AC, 2.54
drill 0.914 pad 1.6 round: A1 154.94,39.37
drill 0.914 pad 1.6 octagon: A2 154.94,36.83; A3 154.94,34.29; A4 154.94,31.75; A5 154.94,29.21; A6 154.94,26.67; A7 154.94,24.13; A8 154.94,21.59; A9 154.94,19.05; A10 154.94,16.51; A11 154.94,13.97; A12 154.94,11.43; A13 154.94,8.89; A14 154.94,6.35; A15 154.94,3.81; A16 154.94,1.27; A17 154.94,-1.27; A18 154.94,-3.81; A19 154.94,-6.35; A20 154.94,-8.89; A21 154.94,-11.43; A22 154.94,-13.97; A23 154.94,-16.51; A24 154.94,-19.05; A25 154.94,-21.59; A26 154.94,-24.13; A27 154.94,-26.67; A28 154.94,-29.21; A29 154.94,-31.75; A30 154.94,-34.29; A31 154.94,-36.83; A32 154.94,-39.37; C1 149.86,39.37; C2 149.86,36.83; C3 149.86,34.29; C4 149.86,31.75; C5 149.86,29.21; C6 149.86,26.67; C7 149.86,24.13; C8 149.86,21.59; C9 149.86,19.05; C10 149.86,16.51; C11 149.86,13.97; C12 149.86,11.43; C13 149.86,8.89; C14 149.86,6.35; C15 149.86,3.81; C16 149.86,1.27; C17 149.86,-1.27; C18 149.86,-3.81; C19 149.86,-6.35; C20 149.86,-8.89; C21 149.86,-11.43; C22 149.86,-13.97; C23 149.86,-16.51; C24 149.86,-19.05; C25 149.86,-21.59; C26 149.86,-24.13; C27 149.86,-26.67; C28 149.86,-29.21; C29 149.86,-31.75; C30 149.86,-34.29; C31 149.86,-36.83; C32 149.86,-39.37
hole 2.794 at 157.48,44.45
hole 2.794 at 157.48,-44.45

## Footprint VG64B (pad centres in mm)
EUROCARD, 4 holes, C/AC, 2.54
drill 0.914 pad 1.6 round: A1 154.94,39.37
drill 0.914 pad 1.6 octagon: A2 154.94,36.83; A3 154.94,34.29; A4 154.94,31.75; A5 154.94,29.21; A6 154.94,26.67; A7 154.94,24.13; A8 154.94,21.59; A9 154.94,19.05; A10 154.94,16.51; A11 154.94,13.97; A12 154.94,11.43; A13 154.94,8.89; A14 154.94,6.35; A15 154.94,3.81; A16 154.94,1.27; A17 154.94,-1.27; A18 154.94,-3.81; A19 154.94,-6.35; A20 154.94,-8.89; A21 154.94,-11.43; A22 154.94,-13.97; A23 154.94,-16.51; A24 154.94,-19.05; A25 154.94,-21.59; A26 154.94,-24.13; A27 154.94,-26.67; A28 154.94,-29.21; A29 154.94,-31.75; A30 154.94,-34.29; A31 154.94,-36.83; A32 154.94,-39.37; C1 149.86,39.37; C2 149.86,36.83; C3 149.86,34.29; C4 149.86,31.75; C5 149.86,29.21; C6 149.86,26.67; C7 149.86,24.13; C8 149.86,21.59; C9 149.86,19.05; C10 149.86,16.51; C11 149.86,13.97; C12 149.86,11.43; C13 149.86,8.89; C14 149.86,6.35; C15 149.86,3.81; C16 149.86,1.27; C17 149.86,-1.27; C18 149.86,-3.81; C19 149.86,-6.35; C20 149.86,-8.89; C21 149.86,-11.43; C22 149.86,-13.97; C23 149.86,-16.51; C24 149.86,-19.05; C25 149.86,-21.59; C26 149.86,-24.13; C27 149.86,-26.67; C28 149.86,-29.21; C29 149.86,-31.75; C30 149.86,-34.29; C31 149.86,-36.83; C32 149.86,-39.37
hole 2.794 at 157.48,44.45
hole 2.794 at 157.48,-44.45
hole 2.794 at 3.81,-44.45
hole 2.794 at 3.81,44.45

## Footprint VG64K (pad centres in mm)
EUROCARD, 2 holes, C/ABC, 2.54
drill 0.914 pad 1.6 round: A1 154.94,39.37
drill 0.914 pad 1.6 octagon: A2 154.94,36.83; A3 154.94,34.29; A4 154.94,31.75; A5 154.94,29.21; A6 154.94,26.67; A7 154.94,24.13; A8 154.94,21.59; A9 154.94,19.05; A10 154.94,16.51; A11 154.94,13.97; A12 154.94,11.43; A13 154.94,8.89; A14 154.94,6.35; A15 154.94,3.81; A16 154.94,1.27; A17 154.94,-1.27; A18 154.94,-3.81; A19 154.94,-6.35; A20 154.94,-8.89; A21 154.94,-11.43; A22 154.94,-13.97; A23 154.94,-16.51; A24 154.94,-19.05; A25 154.94,-21.59; A26 154.94,-24.13; A27 154.94,-26.67; A28 154.94,-29.21; A29 154.94,-31.75; A30 154.94,-34.29; A31 154.94,-36.83; A32 154.94,-39.37; C1 149.86,39.37; C2 149.86,36.83; C3 149.86,34.29; C4 149.86,31.75; C5 149.86,29.21; C6 149.86,26.67; C7 149.86,24.13; C8 149.86,21.59; C9 149.86,19.05; C10 149.86,16.51; C11 149.86,13.97; C12 149.86,11.43; C13 149.86,8.89; C14 149.86,6.35; C15 149.86,3.81; C16 149.86,1.27; C17 149.86,-1.27; C18 149.86,-3.81; C19 149.86,-6.35; C20 149.86,-8.89; C21 149.86,-11.43; C22 149.86,-13.97; C23 149.86,-16.51; C24 149.86,-19.05; C25 149.86,-21.59; C26 149.86,-24.13; C27 149.86,-26.67; C28 149.86,-29.21; C29 149.86,-31.75; C30 149.86,-34.29; C31 149.86,-36.83; C32 149.86,-39.37
hole 2.794 at 157.48,44.45
hole 2.794 at 157.48,-44.45

## Footprint VG64KB (pad centres in mm)
EUROCARD, 4 holes, C/AC, 2.54
drill 0.914 pad 1.6 round: A1 154.94,39.37
drill 0.914 pad 1.6 octagon: A2 154.94,36.83; A3 154.94,34.29; A4 154.94,31.75; A5 154.94,29.21; A6 154.94,26.67; A7 154.94,24.13; A8 154.94,21.59; A9 154.94,19.05; A10 154.94,16.51; A11 154.94,13.97; A12 154.94,11.43; A13 154.94,8.89; A14 154.94,6.35; A15 154.94,3.81; A16 154.94,1.27; A17 154.94,-1.27; A18 154.94,-3.81; A19 154.94,-6.35; A20 154.94,-8.89; A21 154.94,-11.43; A22 154.94,-13.97; A23 154.94,-16.51; A24 154.94,-19.05; A25 154.94,-21.59; A26 154.94,-24.13; A27 154.94,-26.67; A28 154.94,-29.21; A29 154.94,-31.75; A30 154.94,-34.29; A31 154.94,-36.83; A32 154.94,-39.37; C1 149.86,39.37; C2 149.86,36.83; C3 149.86,34.29; C4 149.86,31.75; C5 149.86,29.21; C6 149.86,26.67; C7 149.86,24.13; C8 149.86,21.59; C9 149.86,19.05; C10 149.86,16.51; C11 149.86,13.97; C12 149.86,11.43; C13 149.86,8.89; C14 149.86,6.35; C15 149.86,3.81; C16 149.86,1.27; C17 149.86,-1.27; C18 149.86,-3.81; C19 149.86,-6.35; C20 149.86,-8.89; C21 149.86,-11.43; C22 149.86,-13.97; C23 149.86,-16.51; C24 149.86,-19.05; C25 149.86,-21.59; C26 149.86,-24.13; C27 149.86,-26.67; C28 149.86,-29.21; C29 149.86,-31.75; C30 149.86,-34.29; C31 149.86,-36.83; C32 149.86,-39.37
hole 2.794 at 157.48,44.45
hole 2.794 at 157.48,-44.45
hole 2.794 at 3.81,-44.45
hole 2.794 at 3.81,44.45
